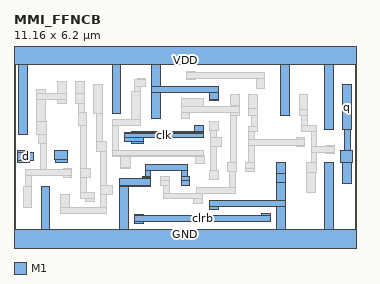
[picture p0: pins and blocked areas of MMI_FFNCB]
MACRO MMI_FFNCB
	CLASS CORE ;
	FOREIGN MMI_FFNCB 0 0 ;
	SIZE 11.16 BY 6.2 ;
	SYMMETRY X Y ;
	SITE CORE1 ;
	PIN d
		DIRECTION input ;
		USE SIGNAL ;
		PORT
			LAYER M1 ;
			RECT 0.12 2.925 0.5 2.98 ;
			LAYER M1 ;
			RECT 0.12 2.645 0.635 2.925 ;
			LAYER M1 ;
			RECT 0.12 2.6 0.5 2.645 ;
		END
		AntennaGateArea 0.3465 ;
	END d
	PIN GND
		DIRECTION inout ;
		USE GROUND ;
		PORT
			LAYER M1 ;
			RECT 4.275 2.345 5.65 2.535 ;
			LAYER M1 ;
			RECT 4.275 2.145 4.465 2.345 ;
			LAYER M1 ;
			RECT 5.455 2.145 5.65 2.345 ;
			LAYER M1 ;
			RECT 8.57 2.24 8.85 2.595 ;
			LAYER M1 ;
			RECT 4.19 2.11 4.47 2.145 ;
			LAYER M1 ;
			RECT 3.45 2.08 3.73 2.085 ;
			LAYER M1 ;
			RECT 4.18 2.08 4.47 2.11 ;
			LAYER M1 ;
			RECT 3.45 1.83 4.47 2.08 ;
			LAYER M1 ;
			RECT 5.455 2.01 5.74 2.145 ;
			LAYER M1 ;
			RECT 5.46 1.83 5.74 2.01 ;
			LAYER M1 ;
			RECT 8.57 1.955 8.86 2.24 ;
			LAYER M1 ;
			RECT 0.885 0.42 1.165 1.82 ;
			LAYER M1 ;
			RECT 3.45 1.795 4.465 1.83 ;
			LAYER M1 ;
			RECT 3.45 0.42 3.73 1.795 ;
			LAYER M1 ;
			RECT 6.385 1.345 6.665 1.35 ;
			LAYER M1 ;
			RECT 8.57 1.345 8.85 1.955 ;
			LAYER M1 ;
			RECT 6.385 1.15 8.85 1.345 ;
			LAYER M1 ;
			RECT 6.385 1.07 6.665 1.15 ;
			LAYER M1 ;
			RECT 8.57 0.42 8.85 1.15 ;
			LAYER M1 ;
			RECT 10.135 0.42 10.415 2.6 ;
			LAYER M1 ;
			RECT 0 -0.42 11.16 0.42 ;
		END
	END GND
	PIN q
		DIRECTION output ;
		USE SIGNAL ;
		PORT
			LAYER M1 ;
			RECT 10.725 3.66 11.005 5.13 ;
			LAYER M1 ;
			RECT 10.775 2.99 10.97 3.66 ;
			LAYER M1 ;
			RECT 10.66 2.61 11.04 2.99 ;
			LAYER M1 ;
			RECT 10.725 1.9 11.005 2.61 ;
		END
		AntennaDiffArea 0.91245 ;
	END q
	PIN VDD
		DIRECTION inout ;
		USE POWER ;
		PORT
			LAYER M1 ;
			RECT 0 5.78 11.16 6.62 ;
			LAYER M1 ;
			RECT 0.16 3.515 0.44 5.78 ;
			LAYER M1 ;
			RECT 3.2 4.205 3.48 5.78 ;
			LAYER M1 ;
			RECT 4.5 5.085 4.78 5.78 ;
			LAYER M1 ;
			RECT 4.5 4.89 6.67 5.085 ;
			LAYER M1 ;
			RECT 4.5 4.025 4.78 4.89 ;
			LAYER M1 ;
			RECT 6.385 4.635 6.67 4.89 ;
			LAYER M1 ;
			RECT 6.385 4.61 6.665 4.635 ;
			LAYER M1 ;
			RECT 8.71 4.115 8.99 5.78 ;
			LAYER M1 ;
			RECT 10.135 3.66 10.415 5.78 ;
		END
	END VDD
	PIN clk
		DIRECTION input ;
		USE CLOCK ;
		PORT
			LAYER M1 ;
			RECT 5.905 3.61 6.185 3.815 ;
			LAYER M1 ;
			RECT 3.84 3.565 6.185 3.61 ;
			LAYER M1 ;
			RECT 3.61 3.535 6.185 3.565 ;
			LAYER M1 ;
			RECT 3.61 3.42 6.18 3.535 ;
			LAYER M1 ;
			RECT 3.61 3.285 4.22 3.42 ;
			LAYER M1 ;
			RECT 3.84 3.23 4.22 3.285 ;
		END
		AntennaGateArea 0.44625 ;
	END clk
	PIN clrb
		DIRECTION input ;
		USE SIGNAL ;
		PORT
			LAYER M1 ;
			RECT 1.36 2.975 1.74 2.98 ;
			LAYER M1 ;
			RECT 1.325 2.695 1.74 2.975 ;
			LAYER M1 ;
			RECT 1.36 2.6 1.74 2.695 ;
			LAYER M1 ;
			RECT 3.935 0.87 4.215 0.9 ;
			LAYER M1 ;
			RECT 8.09 0.87 8.37 0.935 ;
			LAYER M1 ;
			RECT 3.935 0.675 8.37 0.87 ;
			LAYER M1 ;
			RECT 3.935 0.62 4.215 0.675 ;
			LAYER M1 ;
			RECT 8.09 0.655 8.37 0.675 ;
		END
		AntennaGateArea 0.498 ;
	END clrb
	OBS
		LAYER M1 ;
		RECT 0.75 4.85 1.03 4.985 ;
		LAYER M1 ;
		RECT 1.42 4.85 1.7 5.235 ;
		LAYER M1 ;
		RECT 0.75 4.655 1.7 4.85 ;
		LAYER M1 ;
		RECT 0.75 3.925 1.03 4.655 ;
		LAYER M1 ;
		RECT 1.42 4.535 1.7 4.655 ;
		LAYER M1 ;
		RECT 2.01 4.83 2.29 5.235 ;
		LAYER M1 ;
		RECT 2.01 4.535 2.3 4.83 ;
		LAYER M1 ;
		RECT 2.11 4.23 2.3 4.535 ;
		LAYER M1 ;
		RECT 0.75 3.515 1.065 3.925 ;
		LAYER M1 ;
		RECT 2.11 3.805 2.365 4.23 ;
		LAYER M1 ;
		RECT 2.61 4.205 2.89 5.14 ;
		LAYER M1 ;
		RECT 4.015 5.315 4.295 5.34 ;
		LAYER M1 ;
		RECT 3.93 5.06 4.295 5.315 ;
		LAYER M1 ;
		RECT 5.635 5.54 5.915 5.575 ;
		LAYER M1 ;
		RECT 5.635 5.345 8.185 5.54 ;
		LAYER M1 ;
		RECT 5.635 5.295 5.915 5.345 ;
		LAYER M1 ;
		RECT 3.93 4.9 4.12 5.06 ;
		LAYER M1 ;
		RECT 0.805 3.205 1.065 3.515 ;
		LAYER M1 ;
		RECT 0.87 2.36 1.065 3.205 ;
		LAYER M1 ;
		RECT 2.17 2.395 2.365 3.805 ;
		LAYER M1 ;
		RECT 2.695 3.29 2.885 4.205 ;
		LAYER M1 ;
		RECT 3.84 4.005 4.12 4.9 ;
		LAYER M1 ;
		RECT 7.9 5.015 8.185 5.345 ;
		LAYER M1 ;
		RECT 5.585 4.685 6.185 4.69 ;
		LAYER M1 ;
		RECT 5.46 4.41 6.185 4.685 ;
		LAYER M1 ;
		RECT 7.07 4.445 7.35 4.815 ;
		LAYER M1 ;
		RECT 7.06 4.41 7.35 4.445 ;
		LAYER M1 ;
		RECT 5.46 4.215 7.35 4.41 ;
		LAYER M1 ;
		RECT 5.46 4.015 5.74 4.215 ;
		LAYER M1 ;
		RECT 7.06 4.115 7.35 4.215 ;
		LAYER M1 ;
		RECT 7.66 4.35 7.94 4.815 ;
		LAYER M1 ;
		RECT 7.66 4.115 7.95 4.35 ;
		LAYER M1 ;
		RECT 9.3 4.32 9.58 4.815 ;
		LAYER M1 ;
		RECT 9.3 4.115 9.585 4.32 ;
		LAYER M1 ;
		RECT 3.22 3.81 4.12 4.005 ;
		LAYER M1 ;
		RECT 2.695 2.94 3.02 3.29 ;
		LAYER M1 ;
		RECT 1.61 2.36 1.89 2.395 ;
		LAYER M1 ;
		RECT 0.375 2.165 1.89 2.36 ;
		LAYER M1 ;
		RECT 0.375 1.82 0.57 2.165 ;
		LAYER M1 ;
		RECT 1.61 2.115 1.89 2.165 ;
		LAYER M1 ;
		RECT 2.17 2.115 2.48 2.395 ;
		LAYER M1 ;
		RECT 0.295 1.12 0.575 1.82 ;
		LAYER M1 ;
		RECT 2.17 1.625 2.365 2.115 ;
		LAYER M1 ;
		RECT 2.825 1.84 3.02 2.94 ;
		LAYER M1 ;
		RECT 3.22 3 3.41 3.81 ;
		LAYER M1 ;
		RECT 6.385 3.645 6.665 3.925 ;
		LAYER M1 ;
		RECT 6.425 3.405 6.62 3.645 ;
		LAYER M1 ;
		RECT 6.425 3.125 6.765 3.405 ;
		LAYER M1 ;
		RECT 3.22 2.835 6.19 3 ;
		LAYER M1 ;
		RECT 3.22 2.805 6.215 2.835 ;
		LAYER M1 ;
		RECT 3.485 2.445 3.805 2.805 ;
		LAYER M1 ;
		RECT 5.935 2.555 6.215 2.805 ;
		LAYER M1 ;
		RECT 3.49 2.39 3.805 2.445 ;
		LAYER M1 ;
		RECT 6.425 2.32 6.62 3.125 ;
		LAYER M1 ;
		RECT 7.06 2.59 7.255 4.115 ;
		LAYER M1 ;
		RECT 7.755 3.785 7.95 4.115 ;
		LAYER M1 ;
		RECT 7.665 3.59 7.95 3.785 ;
		LAYER M1 ;
		RECT 9.395 3.805 9.585 4.115 ;
		LAYER M1 ;
		RECT 9.395 3.61 9.885 3.805 ;
		LAYER M1 ;
		RECT 7.665 3.355 7.855 3.59 ;
		LAYER M1 ;
		RECT 9.215 3.355 9.495 3.4 ;
		LAYER M1 ;
		RECT 7.665 3.165 9.495 3.355 ;
		LAYER M1 ;
		RECT 7.665 2.59 7.855 3.165 ;
		LAYER M1 ;
		RECT 9.215 3.12 9.495 3.165 ;
		LAYER M1 ;
		RECT 9.695 3.13 9.885 3.61 ;
		LAYER M1 ;
		RECT 10.18 3.13 10.46 3.165 ;
		LAYER M1 ;
		RECT 9.695 2.935 10.46 3.13 ;
		LAYER M1 ;
		RECT 9.695 2.595 9.885 2.935 ;
		LAYER M1 ;
		RECT 10.18 2.885 10.46 2.935 ;
		LAYER M1 ;
		RECT 2.17 1.605 2.54 1.625 ;
		LAYER M1 ;
		RECT 1.52 1.12 1.8 1.555 ;
		LAYER M1 ;
		RECT 2.17 1.435 2.625 1.605 ;
		LAYER M1 ;
		RECT 2.345 1.325 2.625 1.435 ;
		LAYER M1 ;
		RECT 2.825 1.56 3.23 1.84 ;
		LAYER M1 ;
		RECT 4.78 2.02 5.06 2.145 ;
		LAYER M1 ;
		RECT 4.78 1.83 5.065 2.02 ;
		LAYER M1 ;
		RECT 6.385 2.04 6.665 2.32 ;
		LAYER M1 ;
		RECT 6.975 2.31 7.255 2.59 ;
		LAYER M1 ;
		RECT 7.565 2.39 7.855 2.59 ;
		LAYER M1 ;
		RECT 7.565 2.31 7.845 2.39 ;
		LAYER M1 ;
		RECT 2.825 1.12 3.02 1.56 ;
		LAYER M1 ;
		RECT 1.525 0.93 3.02 1.12 ;
		LAYER M1 ;
		RECT 4.875 1.595 5.065 1.83 ;
		LAYER M1 ;
		RECT 7.04 1.785 7.23 2.31 ;
		LAYER M1 ;
		RECT 5.955 1.595 7.23 1.785 ;
		LAYER M1 ;
		RECT 4.875 1.59 7.23 1.595 ;
		LAYER M1 ;
		RECT 9.545 2.275 9.885 2.595 ;
		LAYER M1 ;
		RECT 4.875 1.405 6.145 1.59 ;
		LAYER M1 ;
		RECT 5.865 1.265 6.145 1.405 ;
		LAYER M1 ;
		RECT 9.545 1.625 9.825 2.275 ;
	END
END MMI_FFNCB
